VERSION 5.4 ;
NAMESCASESENSITIVE ON ;
BUSBITCHARS "[]" ;
DIVIDERCHAR "/" ;
UNITS
  DATABASE MICRONS 1000 ;
END UNITS
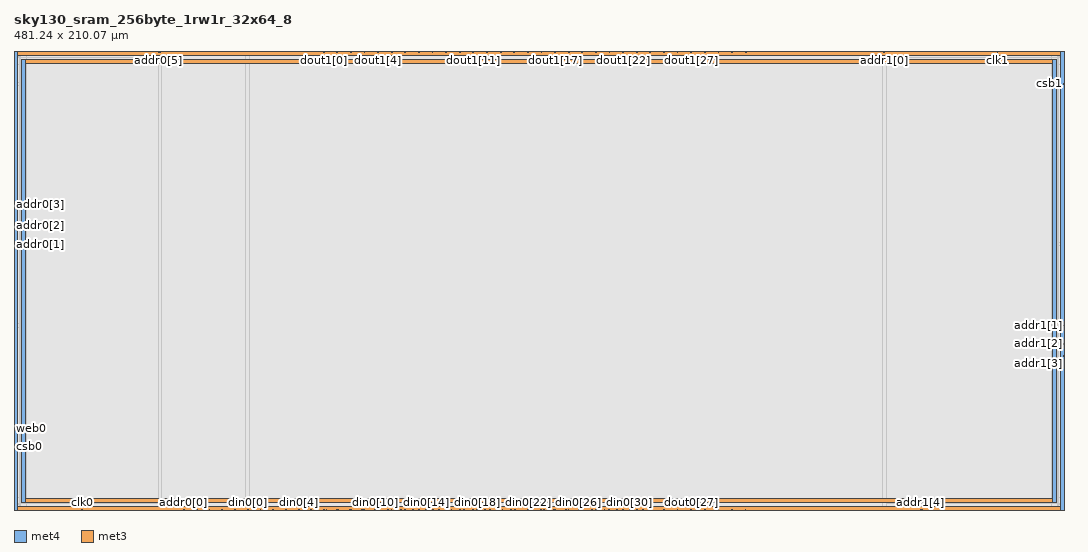
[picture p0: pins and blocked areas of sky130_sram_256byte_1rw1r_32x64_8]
MACRO sky130_sram_256byte_1rw1r_32x64_8
   CLASS BLOCK ;
   SIZE 481.24 BY 210.07 ;
   SYMMETRY X Y R90 ;
   PIN din0[0]
      DIRECTION INPUT ;
      PORT
         LAYER met4 ;
         RECT  106.92 0.0 107.3 0.38 ;
      END
   END din0[0]
   PIN din0[1]
      DIRECTION INPUT ;
      PORT
         LAYER met4 ;
         RECT  112.76 0.0 113.14 0.38 ;
      END
   END din0[1]
   PIN din0[2]
      DIRECTION INPUT ;
      PORT
         LAYER met4 ;
         RECT  118.6 0.0 118.98 0.38 ;
      END
   END din0[2]
   PIN din0[3]
      DIRECTION INPUT ;
      PORT
         LAYER met4 ;
         RECT  124.44 0.0 124.82 0.38 ;
      END
   END din0[3]
   PIN din0[4]
      DIRECTION INPUT ;
      PORT
         LAYER met4 ;
         RECT  130.28 0.0 130.66 0.38 ;
      END
   END din0[4]
   PIN din0[5]
      DIRECTION INPUT ;
      PORT
         LAYER met4 ;
         RECT  136.12 0.0 136.5 0.38 ;
      END
   END din0[5]
   PIN din0[6]
      DIRECTION INPUT ;
      PORT
         LAYER met4 ;
         RECT  141.96 0.0 142.34 0.38 ;
      END
   END din0[6]
   PIN din0[7]
      DIRECTION INPUT ;
      PORT
         LAYER met4 ;
         RECT  147.8 0.0 148.18 0.38 ;
      END
   END din0[7]
   PIN din0[8]
      DIRECTION INPUT ;
      PORT
         LAYER met4 ;
         RECT  153.64 0.0 154.02 0.38 ;
      END
   END din0[8]
   PIN din0[9]
      DIRECTION INPUT ;
      PORT
         LAYER met4 ;
         RECT  159.48 0.0 159.86 0.38 ;
      END
   END din0[9]
   PIN din0[10]
      DIRECTION INPUT ;
      PORT
         LAYER met4 ;
         RECT  165.32 0.0 165.7 0.38 ;
      END
   END din0[10]
   PIN din0[11]
      DIRECTION INPUT ;
      PORT
         LAYER met4 ;
         RECT  171.16 0.0 171.54 0.38 ;
      END
   END din0[11]
   PIN din0[12]
      DIRECTION INPUT ;
      PORT
         LAYER met4 ;
         RECT  177.0 0.0 177.38 0.38 ;
      END
   END din0[12]
   PIN din0[13]
      DIRECTION INPUT ;
      PORT
         LAYER met4 ;
         RECT  182.84 0.0 183.22 0.38 ;
      END
   END din0[13]
   PIN din0[14]
      DIRECTION INPUT ;
      PORT
         LAYER met4 ;
         RECT  188.68 0.0 189.06 0.38 ;
      END
   END din0[14]
   PIN din0[15]
      DIRECTION INPUT ;
      PORT
         LAYER met4 ;
         RECT  194.52 0.0 194.9 0.38 ;
      END
   END din0[15]
   PIN din0[16]
      DIRECTION INPUT ;
      PORT
         LAYER met4 ;
         RECT  200.36 0.0 200.74 0.38 ;
      END
   END din0[16]
   PIN din0[17]
      DIRECTION INPUT ;
      PORT
         LAYER met4 ;
         RECT  206.2 0.0 206.58 0.38 ;
      END
   END din0[17]
   PIN din0[18]
      DIRECTION INPUT ;
      PORT
         LAYER met4 ;
         RECT  212.04 0.0 212.42 0.38 ;
      END
   END din0[18]
   PIN din0[19]
      DIRECTION INPUT ;
      PORT
         LAYER met4 ;
         RECT  217.88 0.0 218.26 0.38 ;
      END
   END din0[19]
   PIN din0[20]
      DIRECTION INPUT ;
      PORT
         LAYER met4 ;
         RECT  223.72 0.0 224.1 0.38 ;
      END
   END din0[20]
   PIN din0[21]
      DIRECTION INPUT ;
      PORT
         LAYER met4 ;
         RECT  229.56 0.0 229.94 0.38 ;
      END
   END din0[21]
   PIN din0[22]
      DIRECTION INPUT ;
      PORT
         LAYER met4 ;
         RECT  235.4 0.0 235.78 0.38 ;
      END
   END din0[22]
   PIN din0[23]
      DIRECTION INPUT ;
      PORT
         LAYER met4 ;
         RECT  241.24 0.0 241.62 0.38 ;
      END
   END din0[23]
   PIN din0[24]
      DIRECTION INPUT ;
      PORT
         LAYER met4 ;
         RECT  247.08 0.0 247.46 0.38 ;
      END
   END din0[24]
   PIN din0[25]
      DIRECTION INPUT ;
      PORT
         LAYER met4 ;
         RECT  252.92 0.0 253.3 0.38 ;
      END
   END din0[25]
   PIN din0[26]
      DIRECTION INPUT ;
      PORT
         LAYER met4 ;
         RECT  258.76 0.0 259.14 0.38 ;
      END
   END din0[26]
   PIN din0[27]
      DIRECTION INPUT ;
      PORT
         LAYER met4 ;
         RECT  264.6 0.0 264.98 0.38 ;
      END
   END din0[27]
   PIN din0[28]
      DIRECTION INPUT ;
      PORT
         LAYER met4 ;
         RECT  270.44 0.0 270.82 0.38 ;
      END
   END din0[28]
   PIN din0[29]
      DIRECTION INPUT ;
      PORT
         LAYER met4 ;
         RECT  276.28 0.0 276.66 0.38 ;
      END
   END din0[29]
   PIN din0[30]
      DIRECTION INPUT ;
      PORT
         LAYER met4 ;
         RECT  282.12 0.0 282.5 0.38 ;
      END
   END din0[30]
   PIN din0[31]
      DIRECTION INPUT ;
      PORT
         LAYER met4 ;
         RECT  287.96 0.0 288.34 0.38 ;
      END
   END din0[31]
   PIN addr0[0]
      DIRECTION INPUT ;
      PORT
         LAYER met4 ;
         RECT  77.72 0.0 78.1 0.38 ;
      END
   END addr0[0]
   PIN addr0[1]
      DIRECTION INPUT ;
      PORT
         LAYER met3 ;
         RECT  0.0 121.6 0.38 121.98 ;
      END
   END addr0[1]
   PIN addr0[2]
      DIRECTION INPUT ;
      PORT
         LAYER met3 ;
         RECT  0.0 130.1 0.38 130.48 ;
      END
   END addr0[2]
   PIN addr0[3]
      DIRECTION INPUT ;
      PORT
         LAYER met3 ;
         RECT  0.0 136.275 0.38 136.655 ;
      END
   END addr0[3]
   PIN addr0[4]
      DIRECTION INPUT ;
      PORT
         LAYER met4 ;
         RECT  66.785 209.69 67.165 210.07 ;
      END
   END addr0[4]
   PIN addr0[5]
      DIRECTION INPUT ;
      PORT
         LAYER met4 ;
         RECT  66.04 209.69 66.42 210.07 ;
      END
   END addr0[5]
   PIN addr1[0]
      DIRECTION INPUT ;
      PORT
         LAYER met4 ;
         RECT  398.68 209.69 399.06 210.07 ;
      END
   END addr1[0]
   PIN addr1[1]
      DIRECTION INPUT ;
      PORT
         LAYER met3 ;
         RECT  480.86 84.385 481.24 84.765 ;
      END
   END addr1[1]
   PIN addr1[2]
      DIRECTION INPUT ;
      PORT
         LAYER met3 ;
         RECT  480.86 75.985 481.24 76.365 ;
      END
   END addr1[2]
   PIN addr1[3]
      DIRECTION INPUT ;
      PORT
         LAYER met3 ;
         RECT  480.86 70.49 481.24 70.87 ;
      END
   END addr1[3]
   PIN addr1[4]
      DIRECTION INPUT ;
      PORT
         LAYER met4 ;
         RECT  415.455 0.0 415.835 0.38 ;
      END
   END addr1[4]
   PIN addr1[5]
      DIRECTION INPUT ;
      PORT
         LAYER met4 ;
         RECT  416.2 0.0 416.58 0.38 ;
      END
   END addr1[5]
   PIN csb0
      DIRECTION INPUT ;
      PORT
         LAYER met3 ;
         RECT  0.0 28.89 0.38 29.27 ;
      END
   END csb0
   PIN csb1
      DIRECTION INPUT ;
      PORT
         LAYER met3 ;
         RECT  480.86 195.075 481.24 195.455 ;
      END
   END csb1
   PIN web0
      DIRECTION INPUT ;
      PORT
         LAYER met3 ;
         RECT  0.0 37.39 0.38 37.77 ;
      END
   END web0
   PIN clk0
      DIRECTION INPUT ;
      PORT
         LAYER met4 ;
         RECT  31.1 0.0 31.48 0.38 ;
      END
   END clk0
   PIN clk1
      DIRECTION INPUT ;
      PORT
         LAYER met4 ;
         RECT  450.6 209.69 450.98 210.07 ;
      END
   END clk1
   PIN wmask0[0]
      DIRECTION INPUT ;
      PORT
         LAYER met4 ;
         RECT  83.56 0.0 83.94 0.38 ;
      END
   END wmask0[0]
   PIN wmask0[1]
      DIRECTION INPUT ;
      PORT
         LAYER met4 ;
         RECT  89.4 0.0 89.78 0.38 ;
      END
   END wmask0[1]
   PIN wmask0[2]
      DIRECTION INPUT ;
      PORT
         LAYER met4 ;
         RECT  95.24 0.0 95.62 0.38 ;
      END
   END wmask0[2]
   PIN wmask0[3]
      DIRECTION INPUT ;
      PORT
         LAYER met4 ;
         RECT  101.08 0.0 101.46 0.38 ;
      END
   END wmask0[3]
   PIN dout0[0]
      DIRECTION OUTPUT ;
      PORT
         LAYER met4 ;
         RECT  143.025 0.0 143.405 0.38 ;
      END
   END dout0[0]
   PIN dout0[1]
      DIRECTION OUTPUT ;
      PORT
         LAYER met4 ;
         RECT  148.49 0.0 148.87 0.38 ;
      END
   END dout0[1]
   PIN dout0[2]
      DIRECTION OUTPUT ;
      PORT
         LAYER met4 ;
         RECT  154.33 0.0 154.71 0.38 ;
      END
   END dout0[2]
   PIN dout0[3]
      DIRECTION OUTPUT ;
      PORT
         LAYER met4 ;
         RECT  160.365 0.0 160.745 0.38 ;
      END
   END dout0[3]
   PIN dout0[4]
      DIRECTION OUTPUT ;
      PORT
         LAYER met4 ;
         RECT  166.605 0.0 166.985 0.38 ;
      END
   END dout0[4]
   PIN dout0[5]
      DIRECTION OUTPUT ;
      PORT
         LAYER met4 ;
         RECT  172.845 0.0 173.225 0.38 ;
      END
   END dout0[5]
   PIN dout0[6]
      DIRECTION OUTPUT ;
      PORT
         LAYER met4 ;
         RECT  179.085 0.0 179.465 0.38 ;
      END
   END dout0[6]
   PIN dout0[7]
      DIRECTION OUTPUT ;
      PORT
         LAYER met4 ;
         RECT  185.325 0.0 185.705 0.38 ;
      END
   END dout0[7]
   PIN dout0[8]
      DIRECTION OUTPUT ;
      PORT
         LAYER met4 ;
         RECT  191.82 0.0 192.2 0.38 ;
      END
   END dout0[8]
   PIN dout0[9]
      DIRECTION OUTPUT ;
      PORT
         LAYER met4 ;
         RECT  197.805 0.0 198.185 0.38 ;
      END
   END dout0[9]
   PIN dout0[10]
      DIRECTION OUTPUT ;
      PORT
         LAYER met4 ;
         RECT  204.045 0.0 204.425 0.38 ;
      END
   END dout0[10]
   PIN dout0[11]
      DIRECTION OUTPUT ;
      PORT
         LAYER met4 ;
         RECT  210.235 0.0 210.615 0.38 ;
      END
   END dout0[11]
   PIN dout0[12]
      DIRECTION OUTPUT ;
      PORT
         LAYER met4 ;
         RECT  215.84 0.0 216.22 0.38 ;
      END
   END dout0[12]
   PIN dout0[13]
      DIRECTION OUTPUT ;
      PORT
         LAYER met4 ;
         RECT  221.915 0.0 222.295 0.38 ;
      END
   END dout0[13]
   PIN dout0[14]
      DIRECTION OUTPUT ;
      PORT
         LAYER met4 ;
         RECT  227.755 0.0 228.135 0.38 ;
      END
   END dout0[14]
   PIN dout0[15]
      DIRECTION OUTPUT ;
      PORT
         LAYER met4 ;
         RECT  236.625 0.0 237.005 0.38 ;
      END
   END dout0[15]
   PIN dout0[16]
      DIRECTION OUTPUT ;
      PORT
         LAYER met4 ;
         RECT  242.865 0.0 243.245 0.38 ;
      END
   END dout0[16]
   PIN dout0[17]
      DIRECTION OUTPUT ;
      PORT
         LAYER met4 ;
         RECT  247.785 0.0 248.165 0.38 ;
      END
   END dout0[17]
   PIN dout0[18]
      DIRECTION OUTPUT ;
      PORT
         LAYER met4 ;
         RECT  253.965 0.0 254.345 0.38 ;
      END
   END dout0[18]
   PIN dout0[19]
      DIRECTION OUTPUT ;
      PORT
         LAYER met4 ;
         RECT  260.205 0.0 260.585 0.38 ;
      END
   END dout0[19]
   PIN dout0[20]
      DIRECTION OUTPUT ;
      PORT
         LAYER met4 ;
         RECT  266.445 0.0 266.825 0.38 ;
      END
   END dout0[20]
   PIN dout0[21]
      DIRECTION OUTPUT ;
      PORT
         LAYER met4 ;
         RECT  272.685 0.0 273.065 0.38 ;
      END
   END dout0[21]
   PIN dout0[22]
      DIRECTION OUTPUT ;
      PORT
         LAYER met4 ;
         RECT  278.925 0.0 279.305 0.38 ;
      END
   END dout0[22]
   PIN dout0[23]
      DIRECTION OUTPUT ;
      PORT
         LAYER met4 ;
         RECT  285.165 0.0 285.545 0.38 ;
      END
   END dout0[23]
   PIN dout0[24]
      DIRECTION OUTPUT ;
      PORT
         LAYER met4 ;
         RECT  291.66 0.0 292.04 0.38 ;
      END
   END dout0[24]
   PIN dout0[25]
      DIRECTION OUTPUT ;
      PORT
         LAYER met4 ;
         RECT  297.645 0.0 298.025 0.38 ;
      END
   END dout0[25]
   PIN dout0[26]
      DIRECTION OUTPUT ;
      PORT
         LAYER met4 ;
         RECT  303.885 0.0 304.265 0.38 ;
      END
   END dout0[26]
   PIN dout0[27]
      DIRECTION OUTPUT ;
      PORT
         LAYER met4 ;
         RECT  310.125 0.0 310.505 0.38 ;
      END
   END dout0[27]
   PIN dout0[28]
      DIRECTION OUTPUT ;
      PORT
         LAYER met4 ;
         RECT  316.365 0.0 316.745 0.38 ;
      END
   END dout0[28]
   PIN dout0[29]
      DIRECTION OUTPUT ;
      PORT
         LAYER met4 ;
         RECT  322.605 0.0 322.985 0.38 ;
      END
   END dout0[29]
   PIN dout0[30]
      DIRECTION OUTPUT ;
      PORT
         LAYER met4 ;
         RECT  328.845 0.0 329.225 0.38 ;
      END
   END dout0[30]
   PIN dout0[31]
      DIRECTION OUTPUT ;
      PORT
         LAYER met4 ;
         RECT  335.085 0.0 335.465 0.38 ;
      END
   END dout0[31]
   PIN dout1[0]
      DIRECTION OUTPUT ;
      PORT
         LAYER met4 ;
         RECT  141.705 209.69 142.085 210.07 ;
      END
   END dout1[0]
   PIN dout1[1]
      DIRECTION OUTPUT ;
      PORT
         LAYER met4 ;
         RECT  147.945 209.69 148.325 210.07 ;
      END
   END dout1[1]
   PIN dout1[2]
      DIRECTION OUTPUT ;
      PORT
         LAYER met4 ;
         RECT  154.185 209.69 154.565 210.07 ;
      END
   END dout1[2]
   PIN dout1[3]
      DIRECTION OUTPUT ;
      PORT
         LAYER met4 ;
         RECT  160.425 209.69 160.805 210.07 ;
      END
   END dout1[3]
   PIN dout1[4]
      DIRECTION OUTPUT ;
      PORT
         LAYER met4 ;
         RECT  166.665 209.69 167.045 210.07 ;
      END
   END dout1[4]
   PIN dout1[5]
      DIRECTION OUTPUT ;
      PORT
         LAYER met4 ;
         RECT  172.905 209.69 173.285 210.07 ;
      END
   END dout1[5]
   PIN dout1[6]
      DIRECTION OUTPUT ;
      PORT
         LAYER met4 ;
         RECT  179.145 209.69 179.525 210.07 ;
      END
   END dout1[6]
   PIN dout1[7]
      DIRECTION OUTPUT ;
      PORT
         LAYER met4 ;
         RECT  185.385 209.69 185.765 210.07 ;
      END
   END dout1[7]
   PIN dout1[8]
      DIRECTION OUTPUT ;
      PORT
         LAYER met4 ;
         RECT  191.625 209.69 192.005 210.07 ;
      END
   END dout1[8]
   PIN dout1[9]
      DIRECTION OUTPUT ;
      PORT
         LAYER met4 ;
         RECT  197.865 209.69 198.245 210.07 ;
      END
   END dout1[9]
   PIN dout1[10]
      DIRECTION OUTPUT ;
      PORT
         LAYER met4 ;
         RECT  204.105 209.69 204.485 210.07 ;
      END
   END dout1[10]
   PIN dout1[11]
      DIRECTION OUTPUT ;
      PORT
         LAYER met4 ;
         RECT  210.345 209.69 210.725 210.07 ;
      END
   END dout1[11]
   PIN dout1[12]
      DIRECTION OUTPUT ;
      PORT
         LAYER met4 ;
         RECT  216.585 209.69 216.965 210.07 ;
      END
   END dout1[12]
   PIN dout1[13]
      DIRECTION OUTPUT ;
      PORT
         LAYER met4 ;
         RECT  222.825 209.69 223.205 210.07 ;
      END
   END dout1[13]
   PIN dout1[14]
      DIRECTION OUTPUT ;
      PORT
         LAYER met4 ;
         RECT  229.065 209.69 229.445 210.07 ;
      END
   END dout1[14]
   PIN dout1[15]
      DIRECTION OUTPUT ;
      PORT
         LAYER met4 ;
         RECT  235.305 209.69 235.685 210.07 ;
      END
   END dout1[15]
   PIN dout1[16]
      DIRECTION OUTPUT ;
      PORT
         LAYER met4 ;
         RECT  241.545 209.69 241.925 210.07 ;
      END
   END dout1[16]
   PIN dout1[17]
      DIRECTION OUTPUT ;
      PORT
         LAYER met4 ;
         RECT  247.785 209.69 248.165 210.07 ;
      END
   END dout1[17]
   PIN dout1[18]
      DIRECTION OUTPUT ;
      PORT
         LAYER met4 ;
         RECT  254.025 209.69 254.405 210.07 ;
      END
   END dout1[18]
   PIN dout1[19]
      DIRECTION OUTPUT ;
      PORT
         LAYER met4 ;
         RECT  260.265 209.69 260.645 210.07 ;
      END
   END dout1[19]
   PIN dout1[20]
      DIRECTION OUTPUT ;
      PORT
         LAYER met4 ;
         RECT  266.505 209.69 266.885 210.07 ;
      END
   END dout1[20]
   PIN dout1[21]
      DIRECTION OUTPUT ;
      PORT
         LAYER met4 ;
         RECT  272.745 209.69 273.125 210.07 ;
      END
   END dout1[21]
   PIN dout1[22]
      DIRECTION OUTPUT ;
      PORT
         LAYER met4 ;
         RECT  278.985 209.69 279.365 210.07 ;
      END
   END dout1[22]
   PIN dout1[23]
      DIRECTION OUTPUT ;
      PORT
         LAYER met4 ;
         RECT  285.225 209.69 285.605 210.07 ;
      END
   END dout1[23]
   PIN dout1[24]
      DIRECTION OUTPUT ;
      PORT
         LAYER met4 ;
         RECT  291.465 209.69 291.845 210.07 ;
      END
   END dout1[24]
   PIN dout1[25]
      DIRECTION OUTPUT ;
      PORT
         LAYER met4 ;
         RECT  297.705 209.69 298.085 210.07 ;
      END
   END dout1[25]
   PIN dout1[26]
      DIRECTION OUTPUT ;
      PORT
         LAYER met4 ;
         RECT  303.945 209.69 304.325 210.07 ;
      END
   END dout1[26]
   PIN dout1[27]
      DIRECTION OUTPUT ;
      PORT
         LAYER met4 ;
         RECT  310.185 209.69 310.565 210.07 ;
      END
   END dout1[27]
   PIN dout1[28]
      DIRECTION OUTPUT ;
      PORT
         LAYER met4 ;
         RECT  316.425 209.69 316.805 210.07 ;
      END
   END dout1[28]
   PIN dout1[29]
      DIRECTION OUTPUT ;
      PORT
         LAYER met4 ;
         RECT  322.665 209.69 323.045 210.07 ;
      END
   END dout1[29]
   PIN dout1[30]
      DIRECTION OUTPUT ;
      PORT
         LAYER met4 ;
         RECT  328.905 209.69 329.285 210.07 ;
      END
   END dout1[30]
   PIN dout1[31]
      DIRECTION OUTPUT ;
      PORT
         LAYER met4 ;
         RECT  335.145 209.69 335.525 210.07 ;
      END
   END dout1[31]
   PIN vccd1
      DIRECTION INOUT ;
      USE POWER ; 
      SHAPE ABUTMENT ; 
      PORT
         LAYER met4 ;
         RECT  0.0 0.0 1.74 210.07 ;
         LAYER met4 ;
         RECT  479.5 0.0 481.24 210.07 ;
         LAYER met3 ;
         RECT  0.0 0.0 481.24 1.74 ;
         LAYER met3 ;
         RECT  0.0 208.33 481.24 210.07 ;
      END
   END vccd1
   PIN vssd1
      DIRECTION INOUT ;
      USE GROUND ; 
      SHAPE ABUTMENT ; 
      PORT
         LAYER met3 ;
         RECT  3.48 3.48 477.76 5.22 ;
         LAYER met4 ;
         RECT  476.02 3.48 477.76 206.59 ;
         LAYER met3 ;
         RECT  3.48 204.85 477.76 206.59 ;
         LAYER met4 ;
         RECT  3.48 3.48 5.22 206.59 ;
      END
   END vssd1
   OBS
   LAYER  met1 ;
      RECT  0.62 0.62 480.62 209.45 ;
   LAYER  met2 ;
      RECT  0.62 0.62 480.62 209.45 ;
   LAYER  met3 ;
      RECT  0.98 121.0 480.62 122.58 ;
      RECT  0.62 122.58 0.98 129.5 ;
      RECT  0.62 131.08 0.98 135.675 ;
      RECT  0.98 83.785 480.26 85.365 ;
      RECT  0.98 85.365 480.26 121.0 ;
      RECT  480.26 85.365 480.62 121.0 ;
      RECT  480.26 76.965 480.62 83.785 ;
      RECT  480.26 71.47 480.62 75.385 ;
      RECT  0.98 122.58 480.26 194.475 ;
      RECT  0.98 194.475 480.26 196.055 ;
      RECT  480.26 122.58 480.62 194.475 ;
      RECT  0.62 29.87 0.98 36.79 ;
      RECT  0.62 38.37 0.98 121.0 ;
      RECT  480.26 2.34 480.62 69.89 ;
      RECT  0.62 2.34 0.98 28.29 ;
      RECT  0.62 137.255 0.98 207.73 ;
      RECT  480.26 196.055 480.62 207.73 ;
      RECT  0.98 2.34 2.88 2.88 ;
      RECT  0.98 2.88 2.88 5.82 ;
      RECT  0.98 5.82 2.88 83.785 ;
      RECT  2.88 2.34 478.36 2.88 ;
      RECT  2.88 5.82 478.36 83.785 ;
      RECT  478.36 2.34 480.26 2.88 ;
      RECT  478.36 2.88 480.26 5.82 ;
      RECT  478.36 5.82 480.26 83.785 ;
      RECT  0.98 196.055 2.88 204.25 ;
      RECT  0.98 204.25 2.88 207.19 ;
      RECT  0.98 207.19 2.88 207.73 ;
      RECT  2.88 196.055 478.36 204.25 ;
      RECT  2.88 207.19 478.36 207.73 ;
      RECT  478.36 196.055 480.26 204.25 ;
      RECT  478.36 204.25 480.26 207.19 ;
      RECT  478.36 207.19 480.26 207.73 ;
   LAYER  met4 ;
      RECT  106.32 0.98 107.9 209.45 ;
      RECT  107.9 0.62 112.16 0.98 ;
      RECT  113.74 0.62 118.0 0.98 ;
      RECT  119.58 0.62 123.84 0.98 ;
      RECT  125.42 0.62 129.68 0.98 ;
      RECT  131.26 0.62 135.52 0.98 ;
      RECT  137.1 0.62 141.36 0.98 ;
      RECT  230.54 0.62 234.8 0.98 ;
      RECT  66.185 0.98 67.765 209.09 ;
      RECT  67.765 0.98 106.32 209.09 ;
      RECT  67.765 209.09 106.32 209.45 ;
      RECT  107.9 0.98 398.08 209.09 ;
      RECT  398.08 0.98 399.66 209.09 ;
      RECT  32.08 0.62 77.12 0.98 ;
      RECT  399.66 209.09 450.0 209.45 ;
      RECT  78.7 0.62 82.96 0.98 ;
      RECT  84.54 0.62 88.8 0.98 ;
      RECT  90.38 0.62 94.64 0.98 ;
      RECT  96.22 0.62 100.48 0.98 ;
      RECT  102.06 0.62 106.32 0.98 ;
      RECT  144.005 0.62 147.2 0.98 ;
      RECT  149.47 0.62 153.04 0.98 ;
      RECT  155.31 0.62 158.88 0.98 ;
      RECT  161.345 0.62 164.72 0.98 ;
      RECT  167.585 0.62 170.56 0.98 ;
      RECT  172.14 0.62 172.245 0.98 ;
      RECT  173.825 0.62 176.4 0.98 ;
      RECT  177.98 0.62 178.485 0.98 ;
      RECT  180.065 0.62 182.24 0.98 ;
      RECT  183.82 0.62 184.725 0.98 ;
      RECT  186.305 0.62 188.08 0.98 ;
      RECT  189.66 0.62 191.22 0.98 ;
      RECT  192.8 0.62 193.92 0.98 ;
      RECT  195.5 0.62 197.205 0.98 ;
      RECT  198.785 0.62 199.76 0.98 ;
      RECT  201.34 0.62 203.445 0.98 ;
      RECT  205.025 0.62 205.6 0.98 ;
      RECT  207.18 0.62 209.635 0.98 ;
      RECT  211.215 0.62 211.44 0.98 ;
      RECT  213.02 0.62 215.24 0.98 ;
      RECT  216.82 0.62 217.28 0.98 ;
      RECT  218.86 0.62 221.315 0.98 ;
      RECT  222.895 0.62 223.12 0.98 ;
      RECT  224.7 0.62 227.155 0.98 ;
      RECT  228.735 0.62 228.96 0.98 ;
      RECT  237.605 0.62 240.64 0.98 ;
      RECT  242.22 0.62 242.265 0.98 ;
      RECT  243.845 0.62 246.48 0.98 ;
      RECT  248.765 0.62 252.32 0.98 ;
      RECT  254.945 0.62 258.16 0.98 ;
      RECT  261.185 0.62 264.0 0.98 ;
      RECT  265.58 0.62 265.845 0.98 ;
      RECT  267.425 0.62 269.84 0.98 ;
      RECT  271.42 0.62 272.085 0.98 ;
      RECT  273.665 0.62 275.68 0.98 ;
      RECT  277.26 0.62 278.325 0.98 ;
      RECT  279.905 0.62 281.52 0.98 ;
      RECT  283.1 0.62 284.565 0.98 ;
      RECT  286.145 0.62 287.36 0.98 ;
      RECT  288.94 0.62 291.06 0.98 ;
      RECT  292.64 0.62 297.045 0.98 ;
      RECT  298.625 0.62 303.285 0.98 ;
      RECT  304.865 0.62 309.525 0.98 ;
      RECT  311.105 0.62 315.765 0.98 ;
      RECT  317.345 0.62 322.005 0.98 ;
      RECT  323.585 0.62 328.245 0.98 ;
      RECT  329.825 0.62 334.485 0.98 ;
      RECT  336.065 0.62 414.855 0.98 ;
      RECT  107.9 209.09 141.105 209.45 ;
      RECT  142.685 209.09 147.345 209.45 ;
      RECT  148.925 209.09 153.585 209.45 ;
      RECT  155.165 209.09 159.825 209.45 ;
      RECT  161.405 209.09 166.065 209.45 ;
      RECT  167.645 209.09 172.305 209.45 ;
      RECT  173.885 209.09 178.545 209.45 ;
      RECT  180.125 209.09 184.785 209.45 ;
      RECT  186.365 209.09 191.025 209.45 ;
      RECT  192.605 209.09 197.265 209.45 ;
      RECT  198.845 209.09 203.505 209.45 ;
      RECT  205.085 209.09 209.745 209.45 ;
      RECT  211.325 209.09 215.985 209.45 ;
      RECT  217.565 209.09 222.225 209.45 ;
      RECT  223.805 209.09 228.465 209.45 ;
      RECT  230.045 209.09 234.705 209.45 ;
      RECT  236.285 209.09 240.945 209.45 ;
      RECT  242.525 209.09 247.185 209.45 ;
      RECT  248.765 209.09 253.425 209.45 ;
      RECT  255.005 209.09 259.665 209.45 ;
      RECT  261.245 209.09 265.905 209.45 ;
      RECT  267.485 209.09 272.145 209.45 ;
      RECT  273.725 209.09 278.385 209.45 ;
      RECT  279.965 209.09 284.625 209.45 ;
      RECT  286.205 209.09 290.865 209.45 ;
      RECT  292.445 209.09 297.105 209.45 ;
      RECT  298.685 209.09 303.345 209.45 ;
      RECT  304.925 209.09 309.585 209.45 ;
      RECT  311.165 209.09 315.825 209.45 ;
      RECT  317.405 209.09 322.065 209.45 ;
      RECT  323.645 209.09 328.305 209.45 ;
      RECT  329.885 209.09 334.545 209.45 ;
      RECT  336.125 209.09 398.08 209.45 ;
      RECT  2.34 209.09 65.44 209.45 ;
      RECT  2.34 0.62 30.5 0.98 ;
      RECT  417.18 0.62 478.9 0.98 ;
      RECT  451.58 209.09 478.9 209.45 ;
      RECT  399.66 0.98 475.42 2.88 ;
      RECT  399.66 2.88 475.42 207.19 ;
      RECT  399.66 207.19 475.42 209.09 ;
      RECT  475.42 0.98 478.36 2.88 ;
      RECT  475.42 207.19 478.36 209.09 ;
      RECT  478.36 0.98 478.9 2.88 ;
      RECT  478.36 2.88 478.9 207.19 ;
      RECT  478.36 207.19 478.9 209.09 ;
      RECT  2.34 0.98 2.88 2.88 ;
      RECT  2.34 2.88 2.88 207.19 ;
      RECT  2.34 207.19 2.88 209.09 ;
      RECT  2.88 0.98 5.82 2.88 ;
      RECT  2.88 207.19 5.82 209.09 ;
      RECT  5.82 0.98 66.185 2.88 ;
      RECT  5.82 2.88 66.185 207.19 ;
      RECT  5.82 207.19 66.185 209.09 ;
   END
END    sky130_sram_256byte_1rw1r_32x64_8
END    LIBRARY
